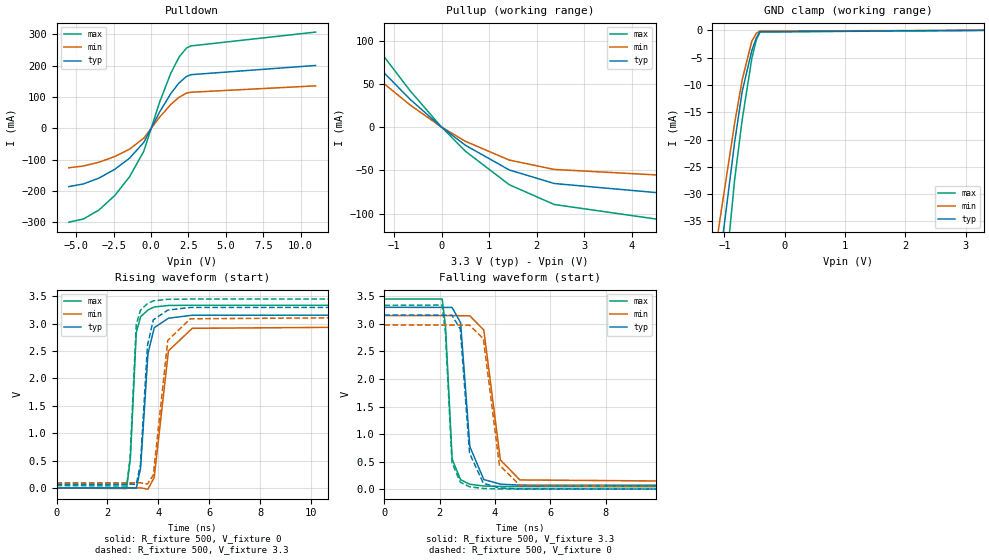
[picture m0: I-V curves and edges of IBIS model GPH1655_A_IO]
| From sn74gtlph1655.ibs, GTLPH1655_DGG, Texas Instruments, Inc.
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[Model]   GPH1655_A_IO
Model_type  I/O
Vinl=0.8
Vinh=2.0
Enable   Active-Low
Vref =   0.0
Rref =   500
Cref =   50p
Vmeas =   1.5
| variable   typ   min   max
C_comp   4.89pF   3.90pF   5.68pF
| C_pullup   5.70pF   4.50pF   6.31pF
| C_pulldown   6.26pF   4.63pF   9.52pF
| C_tri-state   4.89pF   3.90pF   5.68pF
[Temperature Range]   40   100   -40
| Ambient temperature   25   85   -40
[Voltage range]   3.3   3.15   3.45
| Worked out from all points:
|   slope of the pulldown table from 0 to 0.495 V, typ, clamps not added: 10.9 ohm
|   slope of the pullup table from 0 to 0.495 V, typ, clamps not added: 23.9 ohm
|   GND clamp passes 1 mA (typ) near -0.46 V on its own axis
|   rising waveform, R_fixture 500, V_fixture 0: 20-80 % time 269ps typ, 389ps min, 180ps max; typ from 0 V to 3.16 V
|   falling waveform, R_fixture 500, V_fixture 3.3: 20-80 % time 275ps typ, 405ps min, 183ps max; typ from 3.3 V to 0.068 V
|   rising waveform, R_fixture 500, V_fixture 3.3: 20-80 % time 247ps typ, 371ps min, 175ps max; typ from 0.068 V to 3.3 V
|   falling waveform, R_fixture 500, V_fixture 0: 20-80 % time 264ps typ, 390ps min, 178ps max; typ from 3.16 V to 0 V
[GND Clamp]
| GPH1655_A_IO
|   Voltage   I(typ)   I(min)   I(max)
-5.5V     -526.1mA   -431.2mA   -695.1mA
-1.375V   -70.87mA   -58.41mA   -93.3mA
-1.265V   -60.07mA   -49.54mA   -79.12mA
-1.215V   -55.24mA   -45.57mA   -72.77mA
-1.115V   -45.73mA   -37.77mA   -60.28mA
-1.07V    -41.54mA   -34.32mA   -54.77mA
-830mV    -20.44mA   -16.96mA   -27.27mA
-705mV    -11.16mA   -9.047mA   -16.36mA
-545mV    -3.679mA   -1.955mA   -5.104mA
-470mV    -1.345mA   -540.1uA   -1.71mA
-410mV    -262.4uA   -123.9uA   -306.3uA
3.3V      356pA      136.6nA    -8.736nA
[Pulldown]
| GPH1655_A_IO
|   Voltage   I(typ)   I(min)   I(max)
-5.5V     -186mA     -125.9mA   -299.5mA
-4.525V   -177.4mA   -120.3mA   -289.3mA
-3.49V    -158.9mA   -108.3mA   -260.7mA
-2.43V    -130.9mA   -90.06mA   -214.4mA
-1.44V    -95.29mA   -66.51mA   -154.5mA
-490mV    -45.13mA   -31.43mA   -73.34mA
560mV     51.06mA    35.03mA    82.04mA
1.315V    110.5mA    75.78mA    175.4mA
1.875V    145mA      99.16mA    227.4mA
2.375V    165.5mA    112.4mA    256.3mA
2.665V    171mA      115mA      262.7mA
11V       200.4mA    135.3mA    306.8mA
[Pullup]
| GPH1655_A_IO
|   Voltage   I(typ)   I(min)   I(max)
-5.5V     324.7mA    264.4mA    416.5mA
-2.825V   156.8mA    126.6mA    202.3mA
-2.33V    127.1mA    102.3mA    164.2mA
-1.86V    99.4mA     79.79mA    128.7mA
-1.76V    93.59mA    75.08mA    121.2mA
-665mV    32.35mA    25.76mA    42.29mA
-10mV     460.3uA    362uA      606.1uA
500mV     -20.93mA   -16.36mA   -27.8mA
1.42V     -49.41mA   -38.02mA   -66.47mA
2.365V    -65.11mA   -48.86mA   -89.34mA
7.08V     -88.24mA   -62.84mA   -126.4mA
11V       -107.7mA   -74.59mA   -157.7mA
[Ramp]
| GPH1655_A_IO
| variable   typ   min   max
dV/dt_r   1.91/2.84E-10   1.80/4.14E-10   2.01/1.83E-10
dV/dt_f   1.94/2.83E-10   1.84/4.10E-10   2.05/1.85E-10
R_load = 500
[Rising Waveform]
| GPH1655_A_IO
R_fixture =   500
C_fixture =   0
L_fixture =   0
V_fixture =   0
V_fixture_min = 0
V_fixture_max = 0
|   Time   V(typ)   V(min)   V(max)
0s        519.7pV    10.36nV    137.6nV
2.755ns   324.9uV    -6.577uV   -9.436mV
2.905ns   2.141mV    -32.95uV   551.1mV
3.135ns   -5.065mV   1.26mV     2.839V
3.305ns   365.2mV    2.249mV    3.127V
3.595ns   2.45V      -21.34mV   3.251V
3.84ns    2.927V     191mV      3.305V
4.4ns     3.1V       2.503V     3.333V
5.335ns   3.155V     2.916V     3.337V
24.99ns   3.158V     2.979V     3.337V
[Falling Waveform]
| GPH1655_A_IO
R_fixture =   500
C_fixture =   0
L_fixture =   0
V_fixture =   3.3
V_fixture_min = 3.15
V_fixture_max = 3.45
|   Time   V(typ)   V(min)   V(max)
0s        3.3V       3.15V      3.45V
2.09ns    3.299V     3.15V      3.45V
2.21ns    3.298V     3.15V      2.949V
2.45ns    3.297V     3.15V      546.7mV
2.755ns   3.021V     3.148V     171.5mV
3.09ns    773.2mV    3.146V     88.76mV
3.595ns   174.6mV    2.888V     56.75mV
4.195ns   91.17mV    531mV      49.06mV
4.9ns     72.81mV    167.2mV    46.51mV
24.99ns   67.85mV    93.85mV    44.12mV
[Rising Waveform]
| GPH1655_A_IO
R_fixture =   500
C_fixture =   0
L_fixture =   0
V_fixture =   3.3
V_fixture_min = 3.15
V_fixture_max = 3.45
|   Time   V(typ)   V(min)   V(max)
0s        67.81mV    93.67mV    44.1mV
2.755ns   68.13mV    93.67mV    36.43mV
2.89ns    70.93mV    93.64mV    528.1mV
3.135ns   66.1mV     94.85mV    2.986V
3.3ns     433.3mV    95.85mV    3.248V
3.575ns   2.6V       71.8mV     3.366V
3.805ns   3.071V     237mV      3.417V
4.375ns   3.248V     2.696V     3.446V
5.26ns    3.297V     3.09V      3.45V
24.99ns   3.3V       3.15V      3.45V
[Falling Waveform]
| GPH1655_A_IO
R_fixture =   500
C_fixture =   0
L_fixture =   0
V_fixture =   0
V_fixture_min = 0
V_fixture_max = 0
|   Time   V(typ)   V(min)   V(max)
0s        3.159V     2.979V     3.337V
2.085ns   3.158V     2.979V     3.341V
2.205ns   3.157V     2.979V     2.857V
2.445ns   3.156V     2.979V     478.4mV
2.745ns   2.902V     2.978V     126.1mV
3.08ns    651.1mV    2.976V     43.48mV
3.58ns    105.4mV    2.73V      12.48mV
4.16ns    23.1mV     436.1mV    5.055mV
4.91ns    4.568mV    66.69mV    2.361mV
24.99ns   31.9uV     170.5uV    14.85uV
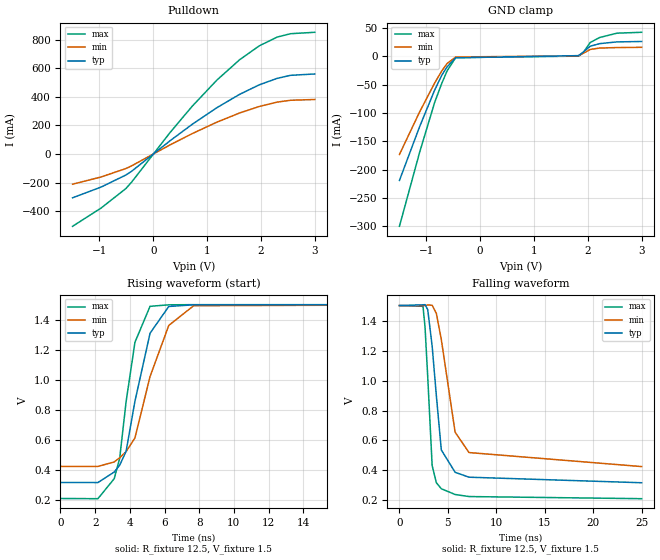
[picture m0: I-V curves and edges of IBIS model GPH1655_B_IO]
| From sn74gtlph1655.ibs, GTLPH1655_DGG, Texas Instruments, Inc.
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[Model]   GPH1655_B_IO
Model_type  I/O_open_drain
Vinl = 0.69
Vinh =1.05
Enable   Active-Low
Vref =   1.5
Rref =   12.5
Cref =   30p
Vmeas =   1
| variable   typ   min   max
C_comp   7.21pF   5.77pF   8.20pF
| C_pulldown   7.56pF   5.86pF   11.77pF
| C_tri-state   7.21pF   5.77pF   8.20pF
[Temperature Range]   40   100   -40
| Ambient temperature   25   85   -40
[Voltage range]   1.5   1.5   1.5
[Pullup Reference]   1.5   1.5   1.5
[POWER Clamp Reference]   1.5   1.5   1.5
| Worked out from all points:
|   slope of the pulldown table from 0 to 0.225 V, typ, clamps not added: 3.34 ohm
|   GND clamp passes 1 mA (typ) near -0.42 V on its own axis
|   rising waveform, R_fixture 12.5, V_fixture 1.5: 20-80 % time 1.18ns typ, 1.52ns min, 879ps max; typ from 0.318 V to 1.5 V
|   falling waveform, R_fixture 12.5, V_fixture 1.5: 20-80 % time 950ps typ, 1.51ns min, 580ps max; typ from 1.5 V to 0.318 V
[GND Clamp]
| GPH1655_B_IO
|   Voltage   I(typ)   I(min)   I(max)
-1.5V     -218.9mA   -173.2mA   -299.8mA
-1.125V   -124.1mA   -98.13mA   -169.4mA
-845mV    -59.51mA   -46.99mA   -81.1mA
-715mV    -33.7mA    -26.13mA   -48.16mA
-615mV    -18.67mA   -12.8mA    -25.89mA
-455mV    -2.655mA   -1.224mA   -2.359mA
1.825V    1.121mA    717.4uA    281.8uA
1.91V     6.975mA    4.926mA    5.866mA
2.045V    17.77mA    12.08mA    24.35mA
2.22V     22.28mA    14.52mA    33.08mA
2.54V     25.36mA    15.35mA    40.73mA
3V        26.07mA    15.81mA    42.31mA
[Pulldown]
| GPH1655_B_IO
|   Voltage   I(typ)   I(min)   I(max)
-1.5V     -307.2mA   -211.7mA   -507mA
-970mV    -232mA     -161.3mA   -379mA
-510mV    -147.7mA   -102.3mA   -242.7mA
-405mV    -121.9mA   -83.75mA   -198.5mA
310mV     92.22mA    63.28mA    149.5mA
720mV     207mA      142.1mA    333.3mA
1.18V     324mA      222.7mA    517.2mA
1.605V    418.1mA    287.4mA    660.7mA
1.97V     484.7mA    333mA      758mA
2.3V      529.8mA    363.3mA    819mA
2.55V     551.1mA    376.4mA    842.9mA
3V        560.7mA    381.7mA    852.8mA
[Ramp]
| GPH1655_B_IO
| variable   typ   min   max
dV/dt_r   0.71/1.20E-09   0.65/1.55E-09   0.77/8.99E-10
dV/dt_f   0.71/9.75E-10   0.65/1.59E-09   0.78/5.98E-10
R_load = 12.5
[Rising Waveform]
| GPH1655_B_IO
R_fixture =   12.5
C_fixture =   0
L_fixture =   0
V_fixture =   1.5
V_fixture_min = 1.5
V_fixture_max = 1.5
|   Time   V(typ)   V(min)   V(max)
0s        318.1mV    425mV      211.8mV
2.16ns    317.9mV    425mV      210.6mV
3.1ns     387.6mV    454.6mV    343.5mV
3.415ns   433.2mV    482.8mV    478.7mV
3.785ns   525.3mV    523.5mV    855.3mV
4.295ns   858.6mV    614.5mV    1.25V
5.165ns   1.31V      1.022V     1.489V
6.245ns   1.488V     1.362V     1.499V
7.68ns    1.499V     1.493V     1.5V
24.99ns   1.5V       1.5V       1.5V
[Falling Waveform]
| GPH1655_B_IO
R_fixture =   12.5
C_fixture =   0
L_fixture =   0
V_fixture =   1.5
V_fixture_min = 1.5
V_fixture_max = 1.5
|   Time   V(typ)   V(min)   V(max)
0s        1.5V       1.5V       1.5V
2.43ns    1.505V     1.5V       1.495V
2.64ns    1.506V     1.5V       1.358V
2.92ns    1.473V     1.504V     1.024V
3.375ns   1.23V      1.502V     433.1mV
3.81ns    898.4mV    1.447V     318.3mV
4.32ns    536.9mV    1.274V     278.2mV
5.745ns   387.9mV    655.5mV    239.8mV
7.175ns   355.2mV    519.6mV    226.1mV
24.99ns   318.2mV    426.1mV    211.9mV
